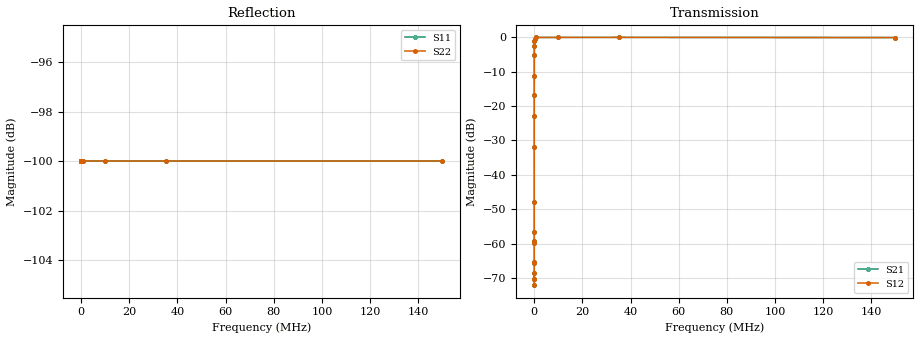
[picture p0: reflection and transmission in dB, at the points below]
! 7/27/2020 12:26 PM
! H:\MS4647B\Production_Data\9437-11\Juan_9\Juan_9_LF_2020-07-27_11-55-57_s2p.s2p
! CORRECTED DATA
# Hz S DB R 50.0
! FREQ  S11DB  S11A  S21DB  S21A  S12DB  S12A  S22DB  S22A
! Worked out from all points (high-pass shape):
!   401 points, 10 Hz to 150 MHz, reference 50 ohm
!   highest |S21| = -0.05 dB at 35.33 MHz (marker M1); lowest = -72.0 dB at 10 Hz (marker M2)
!   |S21| within 3 dB of the highest: 34.84 kHz to end of sweep
!   lowest |S11| = -100.0 dB at 10 Hz (marker M3), VSWR 1.00, Z = 50 + j0 ohm
!   |S11| at or under -10 dB: start of sweep to end of sweep
!   |S22| runs from -100.0 to -100.0 dB; largest |S21 - S12| = 0
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10  -100.00 0.0  -72.01 -72.0  -72.01 -72.0  -100.00 0.0
11.31933  -100.00 0.0  -68.41 -68.4  -68.41 -68.4  -100.00 0.0
13.91624  -100.00 0.0  -70.19 -70.2  -70.19 -70.2  -100.00 0.0
17.83049  -100.00 0.0  -70.35 -70.3  -70.35 -70.3  -100.00 0.0
21.9212  -100.00 0.0  -65.51 -65.5  -65.51 -65.5  -100.00 0.0
26.95042  -100.00 0.0  -65.17 -65.2  -65.17 -65.2  -100.00 0.0
42.45296  -100.00 0.0  -59.67 -59.7  -59.67 -59.7  -100.00 0.0
48.0539  -100.00 0.0  -59.25 -59.2  -59.25 -59.2  -100.00 0.0
59.07855  -100.00 0.0  -56.52 -56.5  -56.52 -56.5  -100.00 0.0
159.2191  -100.00 0.0  -47.75 -47.7  -47.75 -47.7  -100.00 0.0
902.5783  -100.00 0.0  -31.80 -31.8  -31.80 -31.8  -100.00 0.0
2535.074  -100.00 0.0  -22.86 -22.9  -22.86 -22.9  -100.00 0.0
5116.517  -100.00 0.0  -16.88 -16.9  -16.88 -16.9  -100.00 0.0
9908.732  -100.00 0.0  -11.34 -11.3  -11.34 -11.3  -100.00 0.0
22637.2  -100.00 0.0  -5.30 -5.3  -5.30 -5.3  -100.00 0.0
40363.22  -100.00 0.0  -2.48 -2.5  -2.48 -2.5  -100.00 0.0
63581.15  -100.00 0.0  -1.18 -1.2  -1.18 -1.2  -100.00 0.0
108780.6  -100.00 0.0  -0.48 -0.5  -0.48 -0.5  -100.00 0.0
616653.1  -100.00 0.0  -0.07 -0.1  -0.07 -0.1  -100.00 0.0
9818298  -100.00 0.0  -0.06 -0.1  -0.06 -0.1  -100.00 0.0
3.533322e7  -100.00 0.0  -0.05 -0.1  -0.05 -0.1  -100.00 0.0
1.5e8  -100.00 0.0  -0.10 -0.1  -0.10 -0.1  -100.00 0.0
